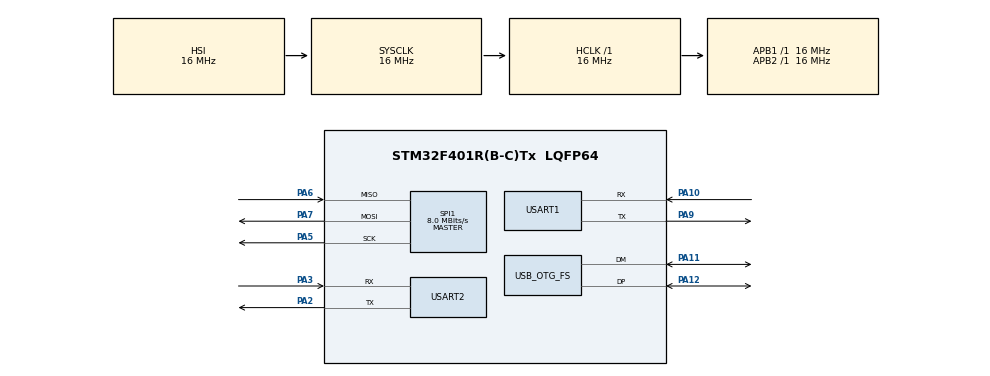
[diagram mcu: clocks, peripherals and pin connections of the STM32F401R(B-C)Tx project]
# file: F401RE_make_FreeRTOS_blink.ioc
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FREERTOS.Tasks01=defaultTask,24,128,StartDefaultTask,Default,NULL,Dynamic,NULL,NULL
Mcu.Family=STM32F4
Mcu.Name=STM32F401R(B-C)Tx
Mcu.Package=LQFP64
NVIC.PriorityGroup=NVIC_PRIORITYGROUP_4
NVIC.TIM1_UP_TIM10_IRQn=true\:15\:0\:false\:false\:true\:false\:false\:true\:true
NVIC.TimeBase=TIM1_UP_TIM10_IRQn
NVIC.TimeBaseIP=TIM1
PA10.Mode=Asynchronous
PA10.Signal=USART1_RX
PA11.Mode=Device_Only
PA11.Signal=USB_OTG_FS_DM
PA12.Mode=Device_Only
PA12.Signal=USB_OTG_FS_DP
PA13.Mode=JTAG_4_pins
PA13.Signal=SYS_JTMS-SWDIO
PA14.Mode=JTAG_4_pins
PA14.Signal=SYS_JTCK-SWCLK
PA15.Mode=JTAG_4_pins
PA15.Signal=SYS_JTDI
PA2.Mode=Asynchronous
PA2.Signal=USART2_TX
PA3.Mode=Asynchronous
PA3.Signal=USART2_RX
PA5.Mode=Full_Duplex_Master
PA5.Signal=SPI1_SCK
PA6.Mode=Full_Duplex_Master
PA6.Signal=SPI1_MISO
PA7.Mode=Full_Duplex_Master
PA7.Signal=SPI1_MOSI
PA9.Mode=Asynchronous
PA9.Signal=USART1_TX
PB3.Mode=JTAG_4_pins
PB3.Signal=SYS_JTDO-SWO
PH0\ -\ OSC_IN.Mode=HSE-External-Oscillator
PH0\ -\ OSC_IN.Signal=RCC_OSC_IN
PH1\ -\ OSC_OUT.Mode=HSE-External-Oscillator
PH1\ -\ OSC_OUT.Signal=RCC_OSC_OUT
ProjectManager.HeapSize=0x200
ProjectManager.StackSize=0x400
ProjectManager.TargetToolchain=Makefile
RCC.48MHZClocksFreq_Value=48000000
RCC.AHBFreq_Value=16000000
RCC.APB1Freq_Value=16000000
RCC.APB2Freq_Value=16000000
RCC.CortexFreq_Value=16000000
RCC.HSE_VALUE=25000000
RCC.HSI_VALUE=16000000
RCC.LSE_VALUE=32768
RCC.PLLM=15
RCC.PLLN=144
RCC.PLLQ=5
RCC.SYSCLKFreq_VALUE=16000000
RCC.VCOOutputFreq_Value=240000000
SPI1.CalculateBaudRate=8.0 MBits/s
SPI1.Direction=SPI_DIRECTION_2LINES
SPI1.Mode=SPI_MODE_MASTER
SPI1.VirtualType=VM_MASTER
USART1.VirtualMode=VM_ASYNC
USART2.VirtualMode=VM_ASYNC
USB_OTG_FS.VirtualMode=Device_Only
VP_FREERTOS_VS_CMSIS_V2.Mode=CMSIS_V2
VP_SYS_VS_tim1.Mode=TIM1
board=custom

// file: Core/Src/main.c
/* USER CODE BEGIN Header */
/**
  ******************************************************************************
  * @file           : main.c
  * @brief          : Main program body
  ******************************************************************************
  * @attention
  *
  * Copyright (c) 2024 STMicroelectronics.
  * All rights reserved.
  *
  * This software is licensed under terms that can be found in the LICENSE file
  * in the root directory of this software component.
  * If no LICENSE file comes with this software, it is provided AS-IS.
  *
  ******************************************************************************
  */
/* USER CODE END Header */
#include "main.h"
#include "cmsis_os.h"
#include "taskBlink.h"

SPI_HandleTypeDef hspi1;

UART_HandleTypeDef huart1;
UART_HandleTypeDef huart2;

PCD_HandleTypeDef hpcd_USB_OTG_FS;

/* Definitions for defaultTask */
osThreadId_t defaultTaskHandle;
const osThreadAttr_t defaultTask_attributes = {
  .name = "defaultTask",
  .stack_size = 128 * 4,
  .priority = (osPriority_t) osPriorityNormal,
};

void SystemClock_Config(void);
static void MX_GPIO_Init(void);
static void MX_SPI1_Init(void);
static void MX_USART1_UART_Init(void);
static void MX_USART2_UART_Init(void);
static void MX_USB_OTG_FS_PCD_Init(void);
void StartDefaultTask(void *argument);

int main(void)
{

  /* MCU Configuration--------------------------------------------------------*/

  /* Reset of all peripherals, Initializes the Flash interface and the Systick. */
  HAL_Init();

  /* Configure the system clock */
  SystemClock_Config();

  /* Initialize all configured peripherals */
  MX_GPIO_Init();
  MX_SPI1_Init();
  MX_USART1_UART_Init();
  MX_USART2_UART_Init();
  MX_USB_OTG_FS_PCD_Init();

  /* Init scheduler */
  osKernelInitialize();

  /* Create the thread(s) */
  /* creation of defaultTask */
  defaultTaskHandle = osThreadNew(StartDefaultTask, NULL, &defaultTask_attributes);

  /* USER CODE BEGIN RTOS_THREADS */
	xTaskCreate( &vGreenBlinkTask,
	             (signed char *)"GreenBlink",
	             configMINIMAL_STACK_SIZE,
	             NULL,
	             1,
	             NULL );

	xTaskCreate( &vRedBlinkTask,
	             (signed char *)"RedBlink",
	             configMINIMAL_STACK_SIZE,
	             NULL,
	             1,
	             NULL );
  /* add threads, ... */
  /* USER CODE END RTOS_THREADS */

  /* Start scheduler */
  osKernelStart();

  /* We should never get here as control is now taken by the scheduler */
  /* Infinite loop */
  while (1)
  {

  }
}

void SystemClock_Config(void)
{
  RCC_OscInitTypeDef RCC_OscInitStruct = {0};
  RCC_ClkInitTypeDef RCC_ClkInitStruct = {0};

  /** Configure the main internal regulator output voltage
  */
  __HAL_RCC_PWR_CLK_ENABLE();
  __HAL_PWR_VOLTAGESCALING_CONFIG(PWR_REGULATOR_VOLTAGE_SCALE2);

  /** Initializes the RCC Oscillators according to the specified parameters
  * in the RCC_OscInitTypeDef structure.
  */
  RCC_OscInitStruct.OscillatorType = RCC_OSCILLATORTYPE_HSI|RCC_OSCILLATORTYPE_HSE;
  RCC_OscInitStruct.HSEState = RCC_HSE_ON;
  RCC_OscInitStruct.HSIState = RCC_HSI_ON;
  RCC_OscInitStruct.HSICalibrationValue = RCC_HSICALIBRATION_DEFAULT;
  RCC_OscInitStruct.PLL.PLLState = RCC_PLL_ON;
  RCC_OscInitStruct.PLL.PLLSource = RCC_PLLSOURCE_HSE;
  RCC_OscInitStruct.PLL.PLLM = 15;
  RCC_OscInitStruct.PLL.PLLN = 144;
  RCC_OscInitStruct.PLL.PLLP = RCC_PLLP_DIV2;
  RCC_OscInitStruct.PLL.PLLQ = 5;
  if (HAL_RCC_OscConfig(&RCC_OscInitStruct) != HAL_OK)
  {
    Error_Handler();
  }

  /** Initializes the CPU, AHB and APB buses clocks
  */
  RCC_ClkInitStruct.ClockType = RCC_CLOCKTYPE_HCLK|RCC_CLOCKTYPE_SYSCLK
                              |RCC_CLOCKTYPE_PCLK1|RCC_CLOCKTYPE_PCLK2;
  RCC_ClkInitStruct.SYSCLKSource   = RCC_SYSCLKSOURCE_HSI;
  RCC_ClkInitStruct.AHBCLKDivider  = RCC_SYSCLK_DIV1;
  RCC_ClkInitStruct.APB1CLKDivider = RCC_HCLK_DIV1;
  RCC_ClkInitStruct.APB2CLKDivider = RCC_HCLK_DIV1;

  if (HAL_RCC_ClockConfig(&RCC_ClkInitStruct, FLASH_LATENCY_0) != HAL_OK)
  {
    Error_Handler();
  }
}

static void MX_SPI1_Init(void)
{

  /* SPI1 parameter configuration*/
  hspi1.Instance               = SPI1;
  hspi1.Init.Mode              = SPI_MODE_MASTER;
  hspi1.Init.Direction         = SPI_DIRECTION_2LINES;
  hspi1.Init.DataSize          = SPI_DATASIZE_8BIT;
  hspi1.Init.CLKPolarity       = SPI_POLARITY_LOW;
  hspi1.Init.CLKPhase          = SPI_PHASE_1EDGE;
  hspi1.Init.NSS               = SPI_NSS_SOFT;
  hspi1.Init.BaudRatePrescaler = SPI_BAUDRATEPRESCALER_2;
  hspi1.Init.FirstBit          = SPI_FIRSTBIT_MSB;
  hspi1.Init.TIMode            = SPI_TIMODE_DISABLE;
  hspi1.Init.CRCCalculation    = SPI_CRCCALCULATION_DISABLE;
  hspi1.Init.CRCPolynomial     = 10;

  if (HAL_SPI_Init(&hspi1) != HAL_OK)
  {
    Error_Handler();
  }

}

static void MX_USART1_UART_Init(void)
{

  huart1.Instance          = USART1;
  huart1.Init.BaudRate     = 115200;
  huart1.Init.WordLength   = UART_WORDLENGTH_8B;
  huart1.Init.StopBits     = UART_STOPBITS_1;
  huart1.Init.Parity       = UART_PARITY_NONE;
  huart1.Init.Mode         = UART_MODE_TX_RX;
  huart1.Init.HwFlowCtl    = UART_HWCONTROL_NONE;
  huart1.Init.OverSampling = UART_OVERSAMPLING_16;
  if (HAL_UART_Init(&huart1) != HAL_OK)
  {
    Error_Handler();
  }

}

static void MX_USART2_UART_Init(void)
{

  huart2.Instance          = USART2;
  huart2.Init.BaudRate     = 115200;
  huart2.Init.WordLength   = UART_WORDLENGTH_8B;
  huart2.Init.StopBits     = UART_STOPBITS_1;
  huart2.Init.Parity       = UART_PARITY_NONE;
  huart2.Init.Mode         = UART_MODE_TX_RX;
  huart2.Init.HwFlowCtl    = UART_HWCONTROL_NONE;
  huart2.Init.OverSampling = UART_OVERSAMPLING_16;

  if (HAL_UART_Init(&huart2) != HAL_OK)
  {
    Error_Handler();
  }

}

static void MX_USB_OTG_FS_PCD_Init(void)
{

  hpcd_USB_OTG_FS.Instance                 = USB_OTG_FS;
  hpcd_USB_OTG_FS.Init.dev_endpoints       = 4;
  hpcd_USB_OTG_FS.Init.speed               = PCD_SPEED_FULL;
  hpcd_USB_OTG_FS.Init.dma_enable          = DISABLE;
  hpcd_USB_OTG_FS.Init.phy_itface          = PCD_PHY_EMBEDDED;
  hpcd_USB_OTG_FS.Init.Sof_enable          = DISABLE;
  hpcd_USB_OTG_FS.Init.low_power_enable    = DISABLE;
  hpcd_USB_OTG_FS.Init.lpm_enable          = DISABLE;
  hpcd_USB_OTG_FS.Init.vbus_sensing_enable = DISABLE;
  hpcd_USB_OTG_FS.Init.use_dedicated_ep1   = DISABLE;

  if (HAL_PCD_Init(&hpcd_USB_OTG_FS) != HAL_OK)
  {
    Error_Handler();
  }

}

static void MX_GPIO_Init(void)
{
  GPIO_InitTypeDef GPIO_InitStruct = {0};

  /* GPIO Ports Clock Enable */
  __HAL_RCC_GPIOH_CLK_ENABLE();
  __HAL_RCC_GPIOA_CLK_ENABLE();
  __HAL_RCC_GPIOB_CLK_ENABLE();
  __HAL_RCC_GPIOC_CLK_ENABLE();

  /*Configure GPIO pin Output Level */
  HAL_GPIO_WritePin(GPIOA, GPIO_PIN_0,  GPIO_PIN_RESET);
  // HAL_GPIO_WritePin(GPIOB, GPIO_PIN_12, GPIO_PIN_RESET);
  HAL_GPIO_WritePin(GPIOC, GPIO_PIN_13, GPIO_PIN_RESET);

  /*Configure GPIO pins : PA00 */
  GPIO_InitStruct.Pin   = GPIO_PIN_0;
  GPIO_InitStruct.Mode  = GPIO_MODE_INPUT;
  GPIO_InitStruct.Pull  = GPIO_PULLDOWN;
  GPIO_InitStruct.Speed = GPIO_SPEED_FREQ_LOW;
  HAL_GPIO_Init(GPIOA, &GPIO_InitStruct);

  /*Configure GPIO pins : PC13 */
  GPIO_InitStruct.Pin   = GPIO_PIN_13;
  GPIO_InitStruct.Mode  = GPIO_MODE_OUTPUT_PP;
  GPIO_InitStruct.Pull  = GPIO_NOPULL;
  GPIO_InitStruct.Speed = GPIO_SPEED_FREQ_LOW;
  HAL_GPIO_Init(GPIOC, &GPIO_InitStruct);

}

void StartDefaultTask(void *argument)
{
  for(;;)
  {
    osDelay(1);
  }
}

void HAL_TIM_PeriodElapsedCallback(TIM_HandleTypeDef *htim)
{
  if (htim->Instance == TIM1) {
    HAL_IncTick();
  }
}

void Error_Handler(void)
{
  __disable_irq();
  while (1)
  {
  }
}
